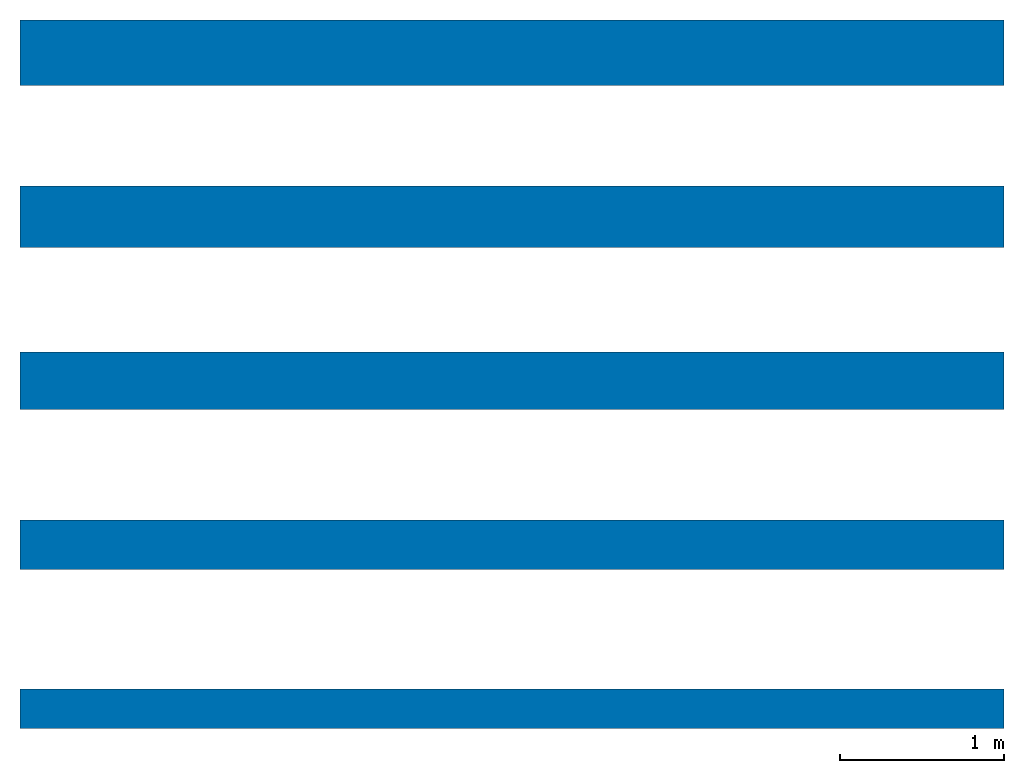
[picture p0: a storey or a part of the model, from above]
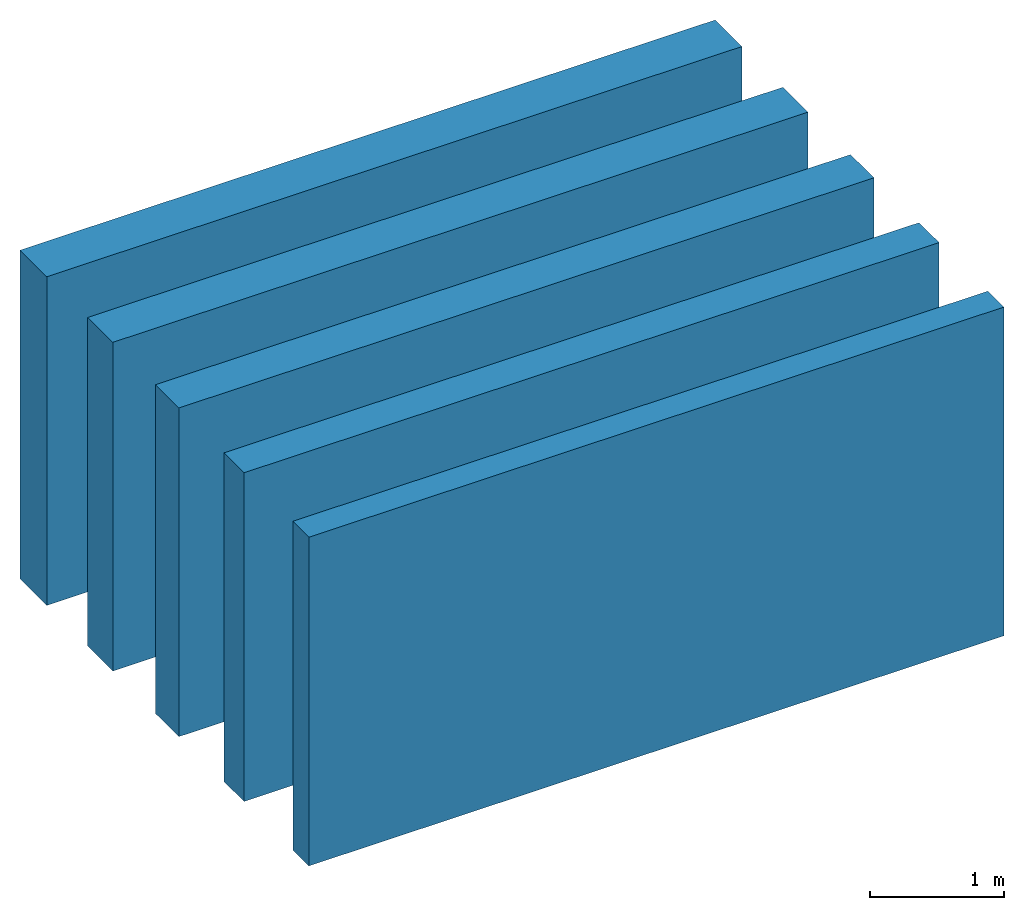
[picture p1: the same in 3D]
Properties of the parts of a building model (IFC2X3)

# File
Description: ViewDefinition [CoordinationView]
File name: Numero
Time: 2019-05-03T09:56:19
Written by: The EXPRESS Data Manager Version 5.02.0100.07 : 28 Aug 2013
Made in: 20150220_1215(x64) - Exporter 16.0.428.0 - Default UI
Comment: STEP Physical File produced by: The EXPRESS Data Manager Version 5.02.0100.07 : 28 Aug 2013 * Module: EDMstepFileFactory/EDMstandAlone * Creation date: Fri May 03 09:56:19 2019 * Host: HP-RS * Database: C:\Users\EKORU_~1\AppData\Local\Temp\{4857D3BD-C62B-48C3-89AA-39043C8533B5}\ifc * Database version: 5507 * Database creation date: Fri May 03 09:56:19 2019 * Schema: IFC2X3 * Model: DataRepository.ifc * Model creation date: Fri May 03 09:56:19 2019 * Header model: DataRepository.ifc_HeaderModel * Header model creation date: Fri May 03 09:56:19 2019 * EDMuser: sdai-user * EDMgroup: sdai-group * License ID and type: 5605 : Permanent license. Expiry date: * EDMstepFileFactory options: 020000

# IfcProject, Numero
LongName: Nome; Phase: Stato

# IfcSite, Default
RefLatitude: 41, 47, 59, 999999; RefLongitude: 12, 35, 59, 999999; RefElevation: 0 mm
Altro - Categoria: Informazioni sul progetto; Data di consegna del progetto: Data; Indirizzo del progetto: Immettere l'indirizzo; Nome del cliente: Proprietario; Nome del progetto: Nome; Numero del progetto: Numero; Stato del progetto: Stato

# IfcBuilding
Pset_BuildingCommon - NumberOfStoreys: 1
Altro - Categoria: Informazioni sul progetto; Data di consegna del progetto: Data; Indirizzo del progetto: Immettere l'indirizzo; Nome del cliente: Proprietario; Nome del progetto: Nome; Numero del progetto: Numero; Stato del progetto: Stato

# IfcBuildingStorey, Livello 1
LongName: Livello 1; Elevation: 0 mm
Vincoli - Base quota altimetrica: Punto base progetto; Quota altimetrica: 0 mm
Altro - Categoria: Livelli; Famiglia: Livello: Estremità 8 mm; Famiglia e tipo: Livello: Estremità 8 mm; ID tipo: Livello: Estremità 8 mm; Tipo: Livello: Estremità 8 mm; Nome famiglia: Livello
Dati identità - Strutturale: no; Nome: Livello 1; Piano edificio: yes; Nome del tipo: Estremità 8 mm
Dimensioni - Altezza di calcolo: 0 mm
Grafica - Colore: 0; Modello di linea: Centro; Simbolo: Estremità del livello - Cerchio: Estremità del livello - Cerchio; Simbolo a estremità 1 per default: no; Simbolo a estremità 2 per default: yes; Spessore di linea: 1

# IfcWallStandardCase: Muro di base:GASBETON Sysmic sp. 240 mm, Muro di base:GASBETON Sysmic sp. 240 mm:128313
In: Livello 1
Type - PredefinedType: STANDARD; Material: GASBETON Sysmic 240 mm
Type - Altro - Categoria: Muri; Nome famiglia: Muro di base
Type - Costruzione - Funzione: Esterno; Ripiegatura agli inserti: Non ripiegare; Ripiegatura alle estremità: Nessuno; Larghezza: 240 mm
Type - Dati identità - Descrizione: muratura formata da blocchi GASBETON Sysmic, densità a secco del singolo blocco 580 kg/mc; Installation Guide: http://www.gasbeton.it/wp-content/uploads/2017/11/GASBETON-Guida-alla-progettazione.pdf; Modello: Muratura Gasbeton Sysmic; Nome del tipo: GASBETON Sysmic sp. 240 mm; Product data url: www.gasbeton.it; Produttore: EKORU s.r.l.; Resistenza al fuoco: REI 180; EI 240; Euroclasse A1; Techinical data sheet: http://www.gasbeton.it/download/sysmic/; URL: http://www.ekoru.it/; Youtube channel: https://www.youtube.com/user/bacchispa
Type - Generale - Edition number: 1; Manufacturer country: Italy; Manufacturer name: EKORU s.r.l.; Product family: walls
Type - Grafica - Colore del retino a dettaglio basso: 0
Type - Materiali e finiture - Materiale strutturale: GASBETON Sysmic; Material main: Autoclaved Aerated Concrete (AAC)
Type - Proprietà analitiche - Ruvidità: 2; Assorbimento: 0.7; Coefficiente di scambio termico (U): 0.541667; Massa termica: 139200; Resistenza termica (R): 1.84615
Altro - Famiglia: Muro di base: GASBETON Sysmic sp. 240 mm; Famiglia e tipo: Muro di base: GASBETON Sysmic sp. 240 mm; ID tipo: Muro di base: GASBETON Sysmic sp. 240 mm; Tipo: Muro di base: GASBETON Sysmic sp. 240 mm
Dimensioni - Area: 18 m2; Lunghezza: 6000 mm; Volume: 4.32 m3
Fasi - Fase di creazione: Fase 1
Strutturale - Attiva modello analitico: no; Strutturale: no; Utilizzo strutturale: Non portante
Vincoli - Delimita il locale: yes; Distanza estensione base: 0 mm; Distanza estensione superiore: 0 mm; La base è associata: no; La parte superiore è associata: no; Linea di ubicazione: Linea d'asse del muro; Offset base: 0 mm; Offset superiore: 0 mm; Relativo a massa: no; Vincolo di base: Livello: Livello 1; Vincolo parte superiore: Livello: Livello 2; Altezza non collegata: 3000 mm
Pset_WallCommon - LoadBearing: no; ExtendToStructure: no; IsExternal: yes; Reference: GASBETON Sysmic sp. 240 mm; FireRating: REI 180; EI 240; Euroclasse A1; ThermalTransmittance: 0.541667 kg/K/s3
Pset_ManufacturerTypeInformation - Manufacturer: EKORU s.r.l.

# IfcWallStandardCase: Muro di base:GASBETON Sysmic sp. 300 mm, Muro di base:GASBETON Sysmic sp. 300 mm:128040
In: Livello 1
Type - PredefinedType: STANDARD; Material: GASBETON Sysmic 300 mm
Type - Altro - Categoria: Muri; Nome famiglia: Muro di base
Type - Costruzione - Funzione: Esterno; Ripiegatura agli inserti: Non ripiegare; Ripiegatura alle estremità: Nessuno; Larghezza: 300 mm
Type - Dati identità - Descrizione: muratura formata da blocchi GASBETON Sysmic, densità a secco del singolo blocco 580 kg/mc; Installation Guide: http://www.gasbeton.it/wp-content/uploads/2017/11/GASBETON-Guida-alla-progettazione.pdf; Modello: Muratura Gasbeton Sysmic; Nome del tipo: GASBETON Sysmic sp. 300 mm; Product data url: https://www.bimobject.com/en/ekoru/product/gasbeton-sysmic-basic; Produttore: EKORU s.r.l.; Resistenza al fuoco: REI 240; Euroclasse A1; Techinical data sheet: http://www.gasbeton.it/download/sysmic/; URL: http://www.ekoru.it/; Youtube channel: https://www.youtube.com/user/bacchispa
Type - Generale - Edition number: 1; Manufacturer country: Italy; Manufacturer name: EKORU s.r.l.; Product family: walls
Type - Grafica - Colore del retino a dettaglio basso: 0
Type - Materiali e finiture - Materiale strutturale: GASBETON Sysmic; Material main: Autoclaved Aerated Concrete (AAC)
Type - Proprietà analitiche - Ruvidità: 2; Assorbimento: 0.7; Coefficiente di scambio termico (U): 0.433333; Massa termica: 174000; Resistenza termica (R): 2.30769
Altro - Famiglia: Muro di base: GASBETON Sysmic sp. 300 mm; Famiglia e tipo: Muro di base: GASBETON Sysmic sp. 300 mm; ID tipo: Muro di base: GASBETON Sysmic sp. 300 mm; Tipo: Muro di base: GASBETON Sysmic sp. 300 mm
Dimensioni - Area: 18 m2; Lunghezza: 6000 mm; Volume: 5.4 m3
Fasi - Fase di creazione: Fase 1
Strutturale - Attiva modello analitico: no; Strutturale: no; Utilizzo strutturale: Non portante
Vincoli - Delimita il locale: yes; Distanza estensione base: 0 mm; Distanza estensione superiore: 0 mm; La base è associata: no; La parte superiore è associata: no; Linea di ubicazione: Linea d'asse del muro; Offset base: 0 mm; Offset superiore: 0 mm; Relativo a massa: no; Vincolo di base: Livello: Livello 1; Vincolo parte superiore: Livello: Livello 2; Altezza non collegata: 3000 mm
Pset_WallCommon - LoadBearing: no; ExtendToStructure: no; IsExternal: yes; Reference: GASBETON Sysmic sp. 300 mm; FireRating: REI 240; Euroclasse A1; ThermalTransmittance: 0.433333 kg/K/s3
Pset_ManufacturerTypeInformation - Manufacturer: EKORU s.r.l.

# IfcWallStandardCase: Muro di base:GASBETON Sysmic sp. 350 mm, Muro di base:GASBETON Sysmic sp. 350 mm:127999
In: Livello 1
Type - PredefinedType: STANDARD; Material: GASBETON Sysmic 350 mm
Type - Altro - Categoria: Muri; Nome famiglia: Muro di base
Type - Costruzione - Funzione: Esterno; Ripiegatura agli inserti: Non ripiegare; Ripiegatura alle estremità: Nessuno; Larghezza: 350 mm
Type - Dati identità - Descrizione: muratura formata da blocchi GASBETON Sysmic, densità a secco del singolo blocco 580 kg/mc; Installation Guide: http://www.gasbeton.it/wp-content/uploads/2017/11/GASBETON-Guida-alla-progettazione.pdf; Modello: Muratura Gasbeton Sysmic; Nome del tipo: GASBETON Sysmic sp. 350 mm; Product data url: https://www.bimobject.com/en/ekoru/product/gasbeton-sysmic-basic; Produttore: EKORU s.r.l.; Resistenza al fuoco: REI 240; Euroclasse A1; Techinical data sheet: http://www.gasbeton.it/download/sysmic/; URL: http://www.ekoru.it/; Youtube channel: https://www.youtube.com/user/bacchispa
Type - Generale - Edition number: 1; Manufacturer country: Italy; Manufacturer name: EKORU s.r.l.; Product family: walls
Type - Grafica - Colore del retino a dettaglio basso: 0
Type - Materiali e finiture - Materiale strutturale: GASBETON Sysmic; Material main: Autoclaved Aerated Concrete (AAC)
Type - Proprietà analitiche - Ruvidità: 2; Assorbimento: 0.7; Coefficiente di scambio termico (U): 0.371429; Massa termica: 203000; Resistenza termica (R): 2.69231
Altro - Famiglia: Muro di base: GASBETON Sysmic sp. 350 mm; Famiglia e tipo: Muro di base: GASBETON Sysmic sp. 350 mm; ID tipo: Muro di base: GASBETON Sysmic sp. 350 mm; Tipo: Muro di base: GASBETON Sysmic sp. 350 mm
Dimensioni - Area: 18 m2; Lunghezza: 6000 mm; Volume: 6.3 m3
Fasi - Fase di creazione: Fase 1
Strutturale - Attiva modello analitico: no; Strutturale: no; Utilizzo strutturale: Non portante
Vincoli - Delimita il locale: yes; Distanza estensione base: 0 mm; Distanza estensione superiore: 0 mm; La base è associata: no; La parte superiore è associata: no; Linea di ubicazione: Linea d'asse del muro; Offset base: 0 mm; Offset superiore: 0 mm; Relativo a massa: no; Vincolo di base: Livello: Livello 1; Vincolo parte superiore: Livello: Livello 2; Altezza non collegata: 3000 mm
Pset_WallCommon - LoadBearing: no; ExtendToStructure: no; IsExternal: yes; Reference: GASBETON Sysmic sp. 350 mm; FireRating: REI 240; Euroclasse A1; ThermalTransmittance: 0.371429 kg/K/s3
Pset_ManufacturerTypeInformation - Manufacturer: EKORU s.r.l.

# IfcWallStandardCase: Muro di base:GASBETON Sysmic sp. 375 mm, Muro di base:GASBETON Sysmic sp. 375 mm:127718
In: Livello 1
Type - PredefinedType: STANDARD; Material: GASBETON Sysmic 375 mm
Type - Altro - Categoria: Muri; Nome famiglia: Muro di base
Type - Costruzione - Funzione: Esterno; Ripiegatura agli inserti: Non ripiegare; Ripiegatura alle estremità: Nessuno; Larghezza: 375 mm
Type - Dati identità - Descrizione: muratura formata da blocchi GASBETON Sysmic, densità a secco del singolo blocco 580 kg/mc; Installation Guide: http://www.gasbeton.it/wp-content/uploads/2017/11/GASBETON-Guida-alla-progettazione.pdf; Modello: Muratura Gasbeton Sysmic; Nome del tipo: GASBETON Sysmic sp. 375 mm; Product data url: www.gasbeton.it; Produttore: EKORU s.r.l.; Resistenza al fuoco: REI 240; Euroclasse A1; Techinical data sheet: http://www.gasbeton.it/download/sysmic/; URL: http://www.ekoru.it/; Youtube channel: https://www.youtube.com/user/bacchispa
Type - Generale - Edition number: 1; Manufacturer country: Italy; Manufacturer name: EKORU s.r.l.; Product family: walls
Type - Grafica - Colore del retino a dettaglio basso: 0
Type - Materiali e finiture - Materiale strutturale: GASBETON Sysmic; Material main: Autoclaved Aerated Concrete (AAC)
Type - Proprietà analitiche - Ruvidità: 2; Assorbimento: 0.7; Coefficiente di scambio termico (U): 0.346667; Massa termica: 217500; Resistenza termica (R): 2.88462
Altro - Famiglia: Muro di base: GASBETON Sysmic sp. 375 mm; Famiglia e tipo: Muro di base: GASBETON Sysmic sp. 375 mm; ID tipo: Muro di base: GASBETON Sysmic sp. 375 mm; Tipo: Muro di base: GASBETON Sysmic sp. 375 mm
Dimensioni - Area: 18 m2; Lunghezza: 6000 mm; Volume: 6.75 m3
Fasi - Fase di creazione: Fase 1
Strutturale - Attiva modello analitico: no; Strutturale: no; Utilizzo strutturale: Non portante
Vincoli - Delimita il locale: yes; Distanza estensione base: 0 mm; Distanza estensione superiore: 0 mm; La base è associata: no; La parte superiore è associata: no; Linea di ubicazione: Linea d'asse del muro; Offset base: 0 mm; Offset superiore: 0 mm; Relativo a massa: no; Vincolo di base: Livello: Livello 1; Vincolo parte superiore: Livello: Livello 2; Altezza non collegata: 3000 mm
Pset_WallCommon - LoadBearing: no; ExtendToStructure: no; IsExternal: yes; Reference: GASBETON Sysmic sp. 375 mm; FireRating: REI 240; Euroclasse A1; ThermalTransmittance: 0.346667 kg/K/s3
Pset_ManufacturerTypeInformation - Manufacturer: EKORU s.r.l.

# IfcWallStandardCase: Muro di base:GASBETON Sysmic sp. 400 mm, Muro di base:GASBETON Sysmic sp. 400 mm:125781
In: Livello 1
Type - PredefinedType: STANDARD; Material: GASBETON Sysmic 400 mm
Type - Altro - Categoria: Muri; Nome famiglia: Muro di base
Type - Costruzione - Funzione: Esterno; Larghezza: 400 mm; Ripiegatura agli inserti: Non ripiegare; Ripiegatura alle estremità: Nessuno
Type - Dati identità - Descrizione: muratura formata da blocchi GASBETON Sysmic, densità a secco del singolo blocco 580 kg/mc; Installation Guide: http://www.gasbeton.it/wp-content/uploads/2017/11/GASBETON-Guida-alla-progettazione.pdf; Modello: Muratura Gasbeton Sysmic; Nome del tipo: GASBETON Sysmic sp. 400 mm; Product data url: https://www.bimobject.com/en/ekoru/product/gasbeton-sysmic-basic; Produttore: EKORU s.r.l.; Resistenza al fuoco: REI 240; Euroclasse A1; Techinical data sheet: http://www.gasbeton.it/download/sysmic/; URL: http://www.ekoru.it/; Youtube channel: https://www.youtube.com/user/bacchispa
Type - Generale - Edition number: 1; Manufacturer country: Italy; Manufacturer name: EKORU s.r.l.; Product family: walls
Type - Grafica - Colore del retino a dettaglio basso: 0
Type - Materiali e finiture - Materiale strutturale: GASBETON Sysmic; Material main: Autoclaved Aerated Concrete (AAC)
Type - Proprietà analitiche - Assorbimento: 0.7; Coefficiente di scambio termico (U): 0.325; Massa termica: 232000; Resistenza termica (R): 3.07692; Ruvidità: 2
Altro - Famiglia: Muro di base: GASBETON Sysmic sp. 400 mm; Famiglia e tipo: Muro di base: GASBETON Sysmic sp. 400 mm; ID tipo: Muro di base: GASBETON Sysmic sp. 400 mm; Tipo: Muro di base: GASBETON Sysmic sp. 400 mm
Dimensioni - Area: 18 m2; Lunghezza: 6000 mm; Volume: 7.2 m3
Fasi - Fase di creazione: Fase 1
Strutturale - Attiva modello analitico: no; Strutturale: no; Utilizzo strutturale: Non portante
Vincoli - Altezza non collegata: 3000 mm; Delimita il locale: yes; Distanza estensione base: 0 mm; Distanza estensione superiore: 0 mm; La base è associata: no; La parte superiore è associata: no; Linea di ubicazione: Linea d'asse del muro; Offset base: 0 mm; Offset superiore: 0 mm; Relativo a massa: no; Vincolo di base: Livello: Livello 1; Vincolo parte superiore: Livello: Livello 2
Pset_WallCommon - Reference: GASBETON Sysmic sp. 400 mm; LoadBearing: no; ExtendToStructure: no; IsExternal: yes; FireRating: REI 240; Euroclasse A1; ThermalTransmittance: 0.325 kg/K/s3
Pset_ManufacturerTypeInformation - Manufacturer: EKORU s.r.l.
